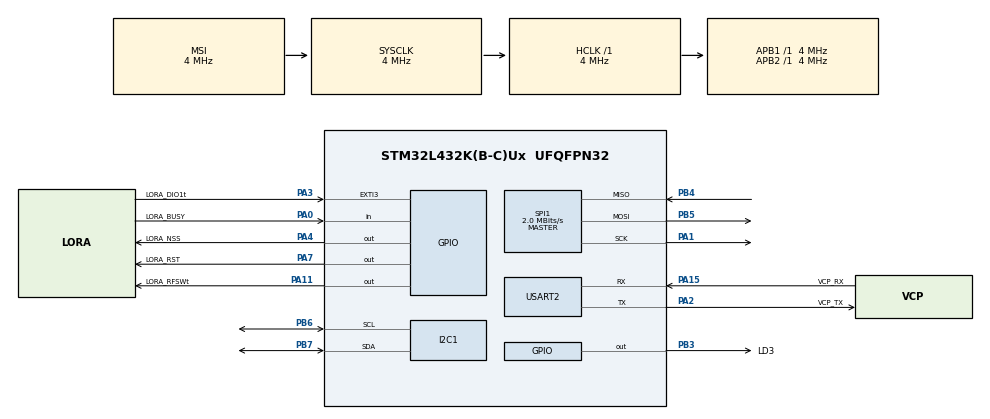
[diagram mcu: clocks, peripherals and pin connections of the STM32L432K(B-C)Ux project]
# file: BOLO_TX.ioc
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I2C1.Timing=0x00100D14
IWDG.Prescaler=IWDG_PRESCALER_256
IWDG.Reload=3124
Mcu.Family=STM32L4
Mcu.Name=STM32L432K(B-C)Ux
Mcu.Package=UFQFPN32
NVIC.EXTI3_IRQn=true\:0\:0\:false\:false\:true\:true\:true\:true
NVIC.PriorityGroup=NVIC_PRIORITYGROUP_4
NVIC.RTC_WKUP_IRQn=true\:0\:0\:false\:false\:true\:true\:true\:true
PA0.GPIO_Label=LORA_BUSY
PA0.Signal=GPIO_Input
PA1.Mode=Full_Duplex_Master
PA1.Signal=SPI1_SCK
PA11.GPIO_Label=LORA_RFSW\t
PA11.PinState=GPIO_PIN_RESET
PA11.Signal=GPIO_Output
PA13\ (JTMS-SWDIO).GPIO_Label=SWDIO
PA13\ (JTMS-SWDIO).Mode=Serial_Wire
PA13\ (JTMS-SWDIO).Signal=SYS_JTMS-SWDIO
PA14\ (JTCK-SWCLK).GPIO_Label=SWCLK
PA14\ (JTCK-SWCLK).Mode=Serial_Wire
PA14\ (JTCK-SWCLK).Signal=SYS_JTCK-SWCLK
PA15\ (JTDI).GPIO_Label=VCP_RX
PA15\ (JTDI).Mode=Asynchronous
PA15\ (JTDI).Signal=USART2_RX
PA2.GPIO_Label=VCP_TX
PA2.Mode=Asynchronous
PA2.Signal=USART2_TX
PA3.GPIO_Label=LORA_DIO1\t
PA3.GPIO_PuPd=GPIO_PULLDOWN
PA3.Signal=GPXTI3
PA4.GPIO_Label=LORA_NSS
PA4.PinState=GPIO_PIN_SET
PA4.Signal=GPIO_Output
PA7.GPIO_Label=LORA_RST
PA7.PinState=GPIO_PIN_SET
PA7.Signal=GPIO_Output
PB3\ (JTDO-TRACESWO).GPIO_Label=LD3
PB3\ (JTDO-TRACESWO).Signal=GPIO_Output
PB4\ (NJTRST).Mode=Full_Duplex_Master
PB4\ (NJTRST).Signal=SPI1_MISO
PB5.Mode=Full_Duplex_Master
PB5.Signal=SPI1_MOSI
PB6.Mode=I2C
PB6.Signal=I2C1_SCL
PB7.Mode=I2C
PB7.Signal=I2C1_SDA
PC14-OSC32_IN\ (PC14).Mode=LSE-External-Oscillator
PC14-OSC32_IN\ (PC14).Signal=RCC_OSC32_IN
PC15-OSC32_OUT\ (PC15).Mode=LSE-External-Oscillator
PC15-OSC32_OUT\ (PC15).Signal=RCC_OSC32_OUT
ProjectManager.HeapSize=0x200
ProjectManager.StackSize=0x400
ProjectManager.TargetToolchain=STM32CubeIDE
RCC.AHBFreq_Value=4000000
RCC.APB1Freq_Value=4000000
RCC.APB1TimFreq_Value=4000000
RCC.APB2Freq_Value=4000000
RCC.APB2TimFreq_Value=4000000
RCC.CortexFreq_Value=4000000
RCC.HCLKFreq_Value=4000000
RCC.HSE_VALUE=8000000
RCC.HSI16_VALUE=16000000
RCC.HSI48_VALUE=48000000
RCC.HSI_VALUE=16000000
RCC.MSI_VALUE=4000000
RCC.PLLMUL=RCC_PLLMUL_4
RCC.PLLN=16
RCC.PWR_Regulator_Voltage_Scale=PWR_REGULATOR_VOLTAGE_SCALE2
RCC.RTCClockSelection=RCC_RTCCLKSOURCE_LSE
RCC.SYSCLKFreq_VALUE=4000000
RCC.VCOOutputFreq_Value=64000000
SPI1.BaudRatePrescaler=SPI_BAUDRATEPRESCALER_2
SPI1.CalculateBaudRate=2.0 MBits/s
SPI1.DataSize=SPI_DATASIZE_8BIT
SPI1.Direction=SPI_DIRECTION_2LINES
SPI1.Mode=SPI_MODE_MASTER
SPI1.NSSPMode=SPI_NSS_PULSE_DISABLE
SPI1.VirtualType=VM_MASTER
USART2.VirtualMode-Asynchronous=VM_ASYNC
VP_IWDG_VS_IWDG.Mode=IWDG_Activate
VP_RTC_VS_RTC_Activate.Mode=RTC_Enabled
VP_RTC_VS_RTC_WakeUp_intern.Mode=WakeUp
board=NUCLEO-L432KC

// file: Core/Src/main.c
/* USER CODE BEGIN Header */
/**
  ******************************************************************************
  * @file           : main.c
  * @brief          : Main program body
  ******************************************************************************
  * @attention
  *
  * Copyright (c) 2026 STMicroelectronics.
  * All rights reserved.
  *
  * This software is licensed under terms that can be found in the LICENSE file
  * in the root directory of this software component.
  * If no LICENSE file comes with this software, it is provided AS-IS.
  *
  ******************************************************************************
  */
/* USER CODE END Header */
#include "main.h"

/* USER CODE BEGIN Includes */
#include "app_bolo.h"
/* USER CODE END Includes */

I2C_HandleTypeDef hi2c1;

IWDG_HandleTypeDef hiwdg;

RTC_HandleTypeDef hrtc;

SPI_HandleTypeDef hspi1;

UART_HandleTypeDef huart2;

void SystemClock_Config(void);
static void MX_GPIO_Init(void);
static void MX_I2C1_Init(void);
static void MX_RTC_Init(void);
static void MX_USART2_UART_Init(void);
static void MX_IWDG_Init(void);
static void MX_SPI1_Init(void);

int main(void)
{

  /* MCU Configuration--------------------------------------------------------*/

  /* Reset of all peripherals, Initializes the Flash interface and the Systick. */
  HAL_Init();

  /* Configure the system clock */
  SystemClock_Config();

  /* Initialize all configured peripherals */
  MX_GPIO_Init();
  MX_I2C1_Init();
  MX_RTC_Init();
  MX_USART2_UART_Init();
  MX_IWDG_Init();
  MX_SPI1_Init();
  /* USER CODE BEGIN 2 */
  app_init(&hi2c1, &huart2, &hrtc, &hiwdg, &hspi1); //son los handles, extructura con toda la configuracion
  /* USER CODE END 2 */

  /* Infinite loop */
  while (1)
  {

    /* USER CODE BEGIN 3 */
    app_run();
  }
  /* USER CODE END 3 */
}

void SystemClock_Config(void)
{
  RCC_OscInitTypeDef RCC_OscInitStruct = {0};
  RCC_ClkInitTypeDef RCC_ClkInitStruct = {0};

  /** Configure the main internal regulator output voltage
  */
  if (HAL_PWREx_ControlVoltageScaling(PWR_REGULATOR_VOLTAGE_SCALE2) != HAL_OK)
  {
    Error_Handler();
  }

  /** Configure LSE Drive Capability
  */
  HAL_PWR_EnableBkUpAccess();
  __HAL_RCC_LSEDRIVE_CONFIG(RCC_LSEDRIVE_LOW);

  /** Initializes the RCC Oscillators according to the specified parameters
  * in the RCC_OscInitTypeDef structure.
  */
  RCC_OscInitStruct.OscillatorType = RCC_OSCILLATORTYPE_LSI|RCC_OSCILLATORTYPE_LSE
                              |RCC_OSCILLATORTYPE_MSI;
  RCC_OscInitStruct.LSEState = RCC_LSE_ON;
  RCC_OscInitStruct.LSIState = RCC_LSI_ON;
  RCC_OscInitStruct.MSIState = RCC_MSI_ON;
  RCC_OscInitStruct.MSICalibrationValue = 0;
  RCC_OscInitStruct.MSIClockRange = RCC_MSIRANGE_6;
  RCC_OscInitStruct.PLL.PLLState = RCC_PLL_NONE;
  if (HAL_RCC_OscConfig(&RCC_OscInitStruct) != HAL_OK)
  {
    Error_Handler();
  }

  /** Initializes the CPU, AHB and APB buses clocks
  */
  RCC_ClkInitStruct.ClockType = RCC_CLOCKTYPE_HCLK|RCC_CLOCKTYPE_SYSCLK
                              |RCC_CLOCKTYPE_PCLK1|RCC_CLOCKTYPE_PCLK2;
  RCC_ClkInitStruct.SYSCLKSource = RCC_SYSCLKSOURCE_MSI;
  RCC_ClkInitStruct.AHBCLKDivider = RCC_SYSCLK_DIV1;
  RCC_ClkInitStruct.APB1CLKDivider = RCC_HCLK_DIV1;
  RCC_ClkInitStruct.APB2CLKDivider = RCC_HCLK_DIV1;

  if (HAL_RCC_ClockConfig(&RCC_ClkInitStruct, FLASH_LATENCY_0) != HAL_OK)
  {
    Error_Handler();
  }

  /** Enable MSI Auto calibration
  */
  HAL_RCCEx_EnableMSIPLLMode();
}

static void MX_I2C1_Init(void)
{

  hi2c1.Instance = I2C1;
  hi2c1.Init.Timing = 0x00100D14;
  hi2c1.Init.OwnAddress1 = 0;
  hi2c1.Init.AddressingMode = I2C_ADDRESSINGMODE_7BIT;
  hi2c1.Init.DualAddressMode = I2C_DUALADDRESS_DISABLE;
  hi2c1.Init.OwnAddress2 = 0;
  hi2c1.Init.OwnAddress2Masks = I2C_OA2_NOMASK;
  hi2c1.Init.GeneralCallMode = I2C_GENERALCALL_DISABLE;
  hi2c1.Init.NoStretchMode = I2C_NOSTRETCH_DISABLE;
  if (HAL_I2C_Init(&hi2c1) != HAL_OK)
  {
    Error_Handler();
  }

  /** Configure Analogue filter
  */
  if (HAL_I2CEx_ConfigAnalogFilter(&hi2c1, I2C_ANALOGFILTER_ENABLE) != HAL_OK)
  {
    Error_Handler();
  }

  /** Configure Digital filter
  */
  if (HAL_I2CEx_ConfigDigitalFilter(&hi2c1, 0) != HAL_OK)
  {
    Error_Handler();
  }

}

static void MX_IWDG_Init(void)
{

  hiwdg.Instance = IWDG;
  hiwdg.Init.Prescaler = IWDG_PRESCALER_256;
  hiwdg.Init.Window = 4095;
  hiwdg.Init.Reload = 3124;
  if (HAL_IWDG_Init(&hiwdg) != HAL_OK)
  {
    Error_Handler();
  }

}

static void MX_RTC_Init(void)
{

  /** Initialize RTC Only
  */
  hrtc.Instance = RTC;
  hrtc.Init.HourFormat = RTC_HOURFORMAT_24;
  hrtc.Init.AsynchPrediv = 127;
  hrtc.Init.SynchPrediv = 255;
  hrtc.Init.OutPut = RTC_OUTPUT_DISABLE;
  hrtc.Init.OutPutRemap = RTC_OUTPUT_REMAP_NONE;
  hrtc.Init.OutPutPolarity = RTC_OUTPUT_POLARITY_HIGH;
  hrtc.Init.OutPutType = RTC_OUTPUT_TYPE_OPENDRAIN;
  if (HAL_RTC_Init(&hrtc) != HAL_OK)
  {
    Error_Handler();
  }

}

static void MX_SPI1_Init(void)
{

  /* SPI1 parameter configuration*/
  hspi1.Instance = SPI1;
  hspi1.Init.Mode = SPI_MODE_MASTER;
  hspi1.Init.Direction = SPI_DIRECTION_2LINES;
  hspi1.Init.DataSize = SPI_DATASIZE_8BIT;
  hspi1.Init.CLKPolarity = SPI_POLARITY_LOW;
  hspi1.Init.CLKPhase = SPI_PHASE_1EDGE;
  hspi1.Init.NSS = SPI_NSS_SOFT;
  hspi1.Init.BaudRatePrescaler = SPI_BAUDRATEPRESCALER_2;
  hspi1.Init.FirstBit = SPI_FIRSTBIT_MSB;
  hspi1.Init.TIMode = SPI_TIMODE_DISABLE;
  hspi1.Init.CRCCalculation = SPI_CRCCALCULATION_DISABLE;
  hspi1.Init.CRCPolynomial = 7;
  hspi1.Init.CRCLength = SPI_CRC_LENGTH_DATASIZE;
  hspi1.Init.NSSPMode = SPI_NSS_PULSE_DISABLE;
  if (HAL_SPI_Init(&hspi1) != HAL_OK)
  {
    Error_Handler();
  }

}

static void MX_USART2_UART_Init(void)
{

  huart2.Instance = USART2;
  huart2.Init.BaudRate = 115200;
  huart2.Init.WordLength = UART_WORDLENGTH_8B;
  huart2.Init.StopBits = UART_STOPBITS_1;
  huart2.Init.Parity = UART_PARITY_NONE;
  huart2.Init.Mode = UART_MODE_TX_RX;
  huart2.Init.HwFlowCtl = UART_HWCONTROL_NONE;
  huart2.Init.OverSampling = UART_OVERSAMPLING_16;
  huart2.Init.OneBitSampling = UART_ONE_BIT_SAMPLE_DISABLE;
  huart2.AdvancedInit.AdvFeatureInit = UART_ADVFEATURE_NO_INIT;
  if (HAL_UART_Init(&huart2) != HAL_OK)
  {
    Error_Handler();
  }

}

static void MX_GPIO_Init(void)
{
  GPIO_InitTypeDef GPIO_InitStruct = {0};

  /* GPIO Ports Clock Enable */
  __HAL_RCC_GPIOC_CLK_ENABLE();
  __HAL_RCC_GPIOA_CLK_ENABLE();
  __HAL_RCC_GPIOB_CLK_ENABLE();
  __HAL_RCC_GPIOH_CLK_ENABLE();

  /*Configure GPIO pin Output Level */
  HAL_GPIO_WritePin(GPIOA, LORA_NSS_Pin|LORA_RST_Pin, GPIO_PIN_SET);

  /*Configure GPIO pin Output Level */
  HAL_GPIO_WritePin(LORA_RFSW_GPIO_Port, LORA_RFSW_Pin, GPIO_PIN_RESET);

  /*Configure GPIO pin Output Level */
  HAL_GPIO_WritePin(LD3_GPIO_Port, LD3_Pin, GPIO_PIN_RESET);

  /*Configure GPIO pin : LORA_BUSY_Pin */
  GPIO_InitStruct.Pin = LORA_BUSY_Pin;
  GPIO_InitStruct.Mode = GPIO_MODE_INPUT;
  GPIO_InitStruct.Pull = GPIO_NOPULL;
  HAL_GPIO_Init(LORA_BUSY_GPIO_Port, &GPIO_InitStruct);

  /*Configure GPIO pin : LORA_DIO1_Pin */
  GPIO_InitStruct.Pin = LORA_DIO1_Pin;
  GPIO_InitStruct.Mode = GPIO_MODE_IT_RISING;
  GPIO_InitStruct.Pull = GPIO_PULLDOWN;
  HAL_GPIO_Init(LORA_DIO1_GPIO_Port, &GPIO_InitStruct);

  /*Configure GPIO pins : LORA_NSS_Pin LORA_RST_Pin LORA_RFSW_Pin */
  GPIO_InitStruct.Pin = LORA_NSS_Pin|LORA_RST_Pin|LORA_RFSW_Pin;
  GPIO_InitStruct.Mode = GPIO_MODE_OUTPUT_PP;
  GPIO_InitStruct.Pull = GPIO_NOPULL;
  GPIO_InitStruct.Speed = GPIO_SPEED_FREQ_LOW;
  HAL_GPIO_Init(GPIOA, &GPIO_InitStruct);

  /*Configure GPIO pins : PA5 PA6 PA8 PA9
                           PA10 PA12 */
  GPIO_InitStruct.Pin = GPIO_PIN_5|GPIO_PIN_6|GPIO_PIN_8|GPIO_PIN_9
                          |GPIO_PIN_10|GPIO_PIN_12;
  GPIO_InitStruct.Mode = GPIO_MODE_ANALOG;
  GPIO_InitStruct.Pull = GPIO_NOPULL;
  HAL_GPIO_Init(GPIOA, &GPIO_InitStruct);

  /*Configure GPIO pins : PB0 PB1 */
  GPIO_InitStruct.Pin = GPIO_PIN_0|GPIO_PIN_1;
  GPIO_InitStruct.Mode = GPIO_MODE_ANALOG;
  GPIO_InitStruct.Pull = GPIO_NOPULL;
  HAL_GPIO_Init(GPIOB, &GPIO_InitStruct);

  /*Configure GPIO pin : LD3_Pin */
  GPIO_InitStruct.Pin = LD3_Pin;
  GPIO_InitStruct.Mode = GPIO_MODE_OUTPUT_PP;
  GPIO_InitStruct.Pull = GPIO_NOPULL;
  GPIO_InitStruct.Speed = GPIO_SPEED_FREQ_LOW;
  HAL_GPIO_Init(LD3_GPIO_Port, &GPIO_InitStruct);

  /*Configure GPIO pin : PH3 */
  GPIO_InitStruct.Pin = GPIO_PIN_3;
  GPIO_InitStruct.Mode = GPIO_MODE_ANALOG;
  GPIO_InitStruct.Pull = GPIO_NOPULL;
  HAL_GPIO_Init(GPIOH, &GPIO_InitStruct);

  /* EXTI interrupt init*/
  HAL_NVIC_SetPriority(EXTI3_IRQn, 0, 0);
  HAL_NVIC_EnableIRQ(EXTI3_IRQn);

}

void Error_Handler(void)
{
  __disable_irq();
  while (1)
  {
  }
}
